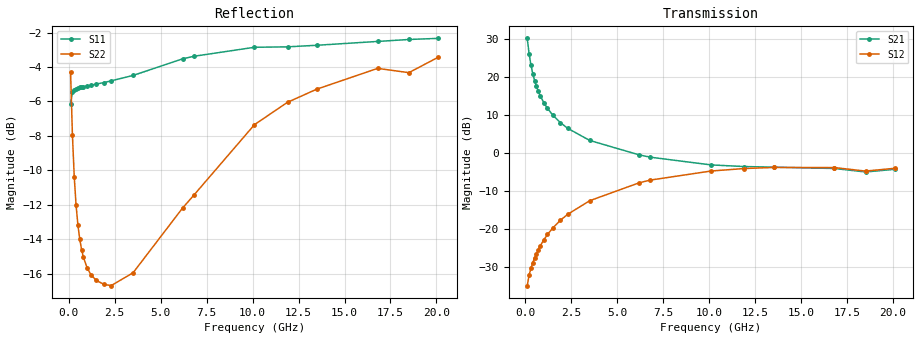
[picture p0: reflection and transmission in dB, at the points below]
!  Infineon Technologies AG
! BFR380L3 , PF131585-7, No.6, Th 09.10.01, soldered on pcb-board, measured with PP GSG850
!  Vce=6.0 V,  Ic=80.0 mA
! Common Emitter S-Parameters:  15. November 2001
#  GHz  S  MA  R  50
! f  S11  S21  S12  S22
! GHz  Mag  Ang  Mag  Ang  Mag  Ang  Mag  Ang
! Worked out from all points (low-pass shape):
!   201 points, 100 MHz to 20.1 GHz, reference 50 ohm
!   highest |S21| = 30.20 dB at 100 MHz (marker M1); lowest = -5.1 dB at 18.5 GHz (marker M2)
!   |S21| within 3 dB of the highest: start of sweep to 174.5 MHz
!   lowest |S11| = -6.1 dB at 100 MHz (marker M3), VSWR 2.95, Z = 27.8 - j36 ohm
!   |S11| at or under -10 dB: nowhere
!   |S22| runs from -16.7 to -3.4 dB; largest |S21 - S12| = 32
!   S11 on the Smith chart (normalised r, x): 100 MHz: 0.56, -0.72; 400 MHz: 0.30, -0.16; 2.3 GHz: 0.29, +0.23; 6.2 GHz: 0.31, +0.73; 11.9 GHz: 0.54, +1.47; 20.1 GHz: 1.13, +2.52
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0.1  0.4941 -96.8  32.37 133.6  0.01766 58.2  0.6095 -38.1
0.2  0.5331 -133.7  20.37 113.5  0.02432 54.0  0.4011 -50.2
0.3  0.5411 -150.0  14.42 104.0  0.02979 55.9  0.3024 -52.9
0.4  0.5459 -159.6  11.08 98.0  0.03533 59.1  0.2499 -53.0
0.5  0.5481 -166.2  8.965 93.8  0.04101 61.9  0.2189 -52.6
0.6  0.5505 -171.1  7.528 90.4  0.04689 63.9  0.1994 -52.0
0.7  0.5512 -175.2  6.491 87.5  0.05266 65.6  0.1859 -51.9
0.8  0.5532 -178.2  5.703 84.9  0.05881 66.8  0.1765 -52.0
1  0.5564 176.2  4.6 80.5  0.07115 68.4  0.1647 -53.2
1.2  0.5581 171.6  3.862 76.5  0.08368 69.0  0.1574 -55.4
1.5  0.5634 165.6  3.125 71.0  0.1027 69.4  0.1513 -59.9
1.9  0.5686 158.6  2.504 64.3  0.1286 68.6  0.1476 -67.5
2.3  0.5754 152.0  2.104 58.1  0.1545 67.3  0.1461 -76.5
3.5  0.5966 135.0  1.456 41.3  0.2336 61.1  0.1593 -104.6
6.2  0.6669 104.3  0.9376 13.8  0.4032 43.0  0.246 -164.9
6.8  0.6782 98.4  0.8753 9.2  0.437 38.4  0.2676 -175.7
10.1  0.7204 73.3  0.6926 -7.6  0.5755 14.6  0.4291 138.9
11.9  0.7225 63.8  0.6591 -13.8  0.6205 2.8  0.4986 119.0
13.5  0.7302 56.6  0.6471 -20.0  0.6412 -7.9  0.5445 104.7
16.8  0.7491 45.5  0.6214 -30.5  0.639 -24.6  0.6255 80.4
18.5  0.759 44.0  0.559 -37.9  0.5744 -32.7  0.6079 74.2
20.1  0.7647 37.2  0.6064 -41.8  0.6252 -38.3  0.6741 63.0
